VERSION 5.7 ;
BUSBITCHARS "[]" ;
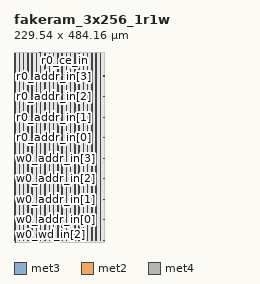
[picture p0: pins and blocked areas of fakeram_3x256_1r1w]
MACRO fakeram_3x256_1r1w
  FOREIGN fakeram_3x256_1r1w 0 0 ;
  SYMMETRY X Y R90 ;
  SIZE 229.540 BY 484.160 ;
  CLASS BLOCK ;
  PIN w0_wd_in[0]
    DIRECTION INPUT ;
    USE SIGNAL ;
    SHAPE ABUTMENT ;
    PORT
      LAYER met3 ;
      RECT 0.000 3.930 0.900 4.230 ;
    END
  END w0_wd_in[0]
  PIN w0_wd_in[1]
    DIRECTION INPUT ;
    USE SIGNAL ;
    SHAPE ABUTMENT ;
    PORT
      LAYER met3 ;
      RECT 228.640 3.930 229.540 4.230 ;
    END
  END w0_wd_in[1]
  PIN w0_wd_in[2]
    DIRECTION OUTPUT ;
    USE SIGNAL ;
    SHAPE ABUTMENT ;
    PORT
      LAYER met2 ;
      RECT 2.690 0.000 2.830 0.420 ;
    END
  END w0_wd_in[2]
  PIN r0_rd_out[0]
    DIRECTION OUTPUT ;
    USE SIGNAL ;
    SHAPE ABUTMENT ;
    PORT
      LAYER met2 ;
      RECT 58.350 0.000 58.490 0.420 ;
    END
  END r0_rd_out[0]
  PIN r0_rd_out[1]
    DIRECTION OUTPUT ;
    USE SIGNAL ;
    SHAPE ABUTMENT ;
    PORT
      LAYER met2 ;
      RECT 114.010 0.000 114.150 0.420 ;
    END
  END r0_rd_out[1]
  PIN r0_rd_out[2]
    DIRECTION OUTPUT ;
    USE SIGNAL ;
    SHAPE ABUTMENT ;
    PORT
      LAYER met2 ;
      RECT 2.690 483.740 2.830 484.160 ;
    END
  END r0_rd_out[2]
  PIN w0_addr_in[0]
    DIRECTION INPUT ;
    USE SIGNAL ;
    SHAPE ABUTMENT ;
    PORT
      LAYER met3 ;
      RECT 0.000 56.290 0.900 56.590 ;
    END
  END w0_addr_in[0]
  PIN w0_addr_in[1]
    DIRECTION INPUT ;
    USE SIGNAL ;
    SHAPE ABUTMENT ;
    PORT
      LAYER met3 ;
      RECT 0.000 108.650 0.900 108.950 ;
    END
  END w0_addr_in[1]
  PIN w0_addr_in[2]
    DIRECTION INPUT ;
    USE SIGNAL ;
    SHAPE ABUTMENT ;
    PORT
      LAYER met3 ;
      RECT 0.000 161.010 0.900 161.310 ;
    END
  END w0_addr_in[2]
  PIN w0_addr_in[3]
    DIRECTION INPUT ;
    USE SIGNAL ;
    SHAPE ABUTMENT ;
    PORT
      LAYER met3 ;
      RECT 0.000 213.370 0.900 213.670 ;
    END
  END w0_addr_in[3]
  PIN w0_addr_in[4]
    DIRECTION INPUT ;
    USE SIGNAL ;
    SHAPE ABUTMENT ;
    PORT
      LAYER met3 ;
      RECT 228.640 56.290 229.540 56.590 ;
    END
  END w0_addr_in[4]
  PIN w0_addr_in[5]
    DIRECTION INPUT ;
    USE SIGNAL ;
    SHAPE ABUTMENT ;
    PORT
      LAYER met3 ;
      RECT 228.640 108.650 229.540 108.950 ;
    END
  END w0_addr_in[5]
  PIN w0_addr_in[6]
    DIRECTION INPUT ;
    USE SIGNAL ;
    SHAPE ABUTMENT ;
    PORT
      LAYER met3 ;
      RECT 228.640 161.010 229.540 161.310 ;
    END
  END w0_addr_in[6]
  PIN w0_addr_in[7]
    DIRECTION INPUT ;
    USE SIGNAL ;
    SHAPE ABUTMENT ;
    PORT
      LAYER met3 ;
      RECT 228.640 213.370 229.540 213.670 ;
    END
  END w0_addr_in[7]
  PIN r0_addr_in[0]
    DIRECTION INPUT ;
    USE SIGNAL ;
    SHAPE ABUTMENT ;
    PORT
      LAYER met3 ;
      RECT 0.000 265.730 0.900 266.030 ;
    END
  END r0_addr_in[0]
  PIN r0_addr_in[1]
    DIRECTION INPUT ;
    USE SIGNAL ;
    SHAPE ABUTMENT ;
    PORT
      LAYER met3 ;
      RECT 0.000 318.090 0.900 318.390 ;
    END
  END r0_addr_in[1]
  PIN r0_addr_in[2]
    DIRECTION INPUT ;
    USE SIGNAL ;
    SHAPE ABUTMENT ;
    PORT
      LAYER met3 ;
      RECT 0.000 370.450 0.900 370.750 ;
    END
  END r0_addr_in[2]
  PIN r0_addr_in[3]
    DIRECTION INPUT ;
    USE SIGNAL ;
    SHAPE ABUTMENT ;
    PORT
      LAYER met3 ;
      RECT 0.000 422.810 0.900 423.110 ;
    END
  END r0_addr_in[3]
  PIN r0_addr_in[4]
    DIRECTION INPUT ;
    USE SIGNAL ;
    SHAPE ABUTMENT ;
    PORT
      LAYER met3 ;
      RECT 228.640 265.730 229.540 266.030 ;
    END
  END r0_addr_in[4]
  PIN r0_addr_in[5]
    DIRECTION INPUT ;
    USE SIGNAL ;
    SHAPE ABUTMENT ;
    PORT
      LAYER met3 ;
      RECT 228.640 318.090 229.540 318.390 ;
    END
  END r0_addr_in[5]
  PIN r0_addr_in[6]
    DIRECTION INPUT ;
    USE SIGNAL ;
    SHAPE ABUTMENT ;
    PORT
      LAYER met3 ;
      RECT 228.640 370.450 229.540 370.750 ;
    END
  END r0_addr_in[6]
  PIN r0_addr_in[7]
    DIRECTION INPUT ;
    USE SIGNAL ;
    SHAPE ABUTMENT ;
    PORT
      LAYER met3 ;
      RECT 228.640 422.810 229.540 423.110 ;
    END
  END r0_addr_in[7]
  PIN w0_we_in
    DIRECTION INPUT ;
    USE SIGNAL ;
    SHAPE ABUTMENT ;
    PORT
      LAYER met2 ;
      RECT 34.430 483.740 34.570 484.160 ;
    END
  END w0_we_in
  PIN w0_ce_in
    DIRECTION INPUT ;
    USE SIGNAL ;
    SHAPE ABUTMENT ;
    PORT
      LAYER met2 ;
      RECT 66.170 483.740 66.310 484.160 ;
    END
  END w0_ce_in
  PIN w0_clk
    DIRECTION INPUT ;
    USE SIGNAL ;
    SHAPE ABUTMENT ;
    PORT
      LAYER met2 ;
      RECT 97.910 483.740 98.050 484.160 ;
    END
  END w0_clk
  PIN r0_ce_in
    DIRECTION INPUT ;
    USE SIGNAL ;
    SHAPE ABUTMENT ;
    PORT
      LAYER met2 ;
      RECT 129.650 483.740 129.790 484.160 ;
    END
  END r0_ce_in
  PIN r0_clk
    DIRECTION INPUT ;
    USE SIGNAL ;
    SHAPE ABUTMENT ;
    PORT
      LAYER met2 ;
      RECT 161.390 483.740 161.530 484.160 ;
    END
  END r0_clk
  PIN VSS
    DIRECTION INOUT ;
    USE GROUND ;
    PORT
      LAYER met4 ;
      RECT 2.160 4.080 3.360 480.080 ;
      RECT 13.040 4.080 14.240 480.080 ;
      RECT 23.920 4.080 25.120 480.080 ;
      RECT 34.800 4.080 36.000 480.080 ;
      RECT 45.680 4.080 46.880 480.080 ;
      RECT 56.560 4.080 57.760 480.080 ;
      RECT 67.440 4.080 68.640 480.080 ;
      RECT 78.320 4.080 79.520 480.080 ;
      RECT 89.200 4.080 90.400 480.080 ;
      RECT 100.080 4.080 101.280 480.080 ;
      RECT 110.960 4.080 112.160 480.080 ;
      RECT 121.840 4.080 123.040 480.080 ;
      RECT 132.720 4.080 133.920 480.080 ;
      RECT 143.600 4.080 144.800 480.080 ;
      RECT 154.480 4.080 155.680 480.080 ;
      RECT 165.360 4.080 166.560 480.080 ;
      RECT 176.240 4.080 177.440 480.080 ;
      RECT 187.120 4.080 188.320 480.080 ;
      RECT 198.000 4.080 199.200 480.080 ;
      RECT 208.880 4.080 210.080 480.080 ;
      RECT 219.760 4.080 220.960 480.080 ;
    END
  END VSS
  PIN VDD
    DIRECTION INOUT ;
    USE POWER ;
    PORT
      LAYER met4 ;
      RECT 2.160 4.080 3.360 480.080 ;
      RECT 13.040 4.080 14.240 480.080 ;
      RECT 23.920 4.080 25.120 480.080 ;
      RECT 34.800 4.080 36.000 480.080 ;
      RECT 45.680 4.080 46.880 480.080 ;
      RECT 56.560 4.080 57.760 480.080 ;
      RECT 67.440 4.080 68.640 480.080 ;
      RECT 78.320 4.080 79.520 480.080 ;
      RECT 89.200 4.080 90.400 480.080 ;
      RECT 100.080 4.080 101.280 480.080 ;
      RECT 110.960 4.080 112.160 480.080 ;
      RECT 121.840 4.080 123.040 480.080 ;
      RECT 132.720 4.080 133.920 480.080 ;
      RECT 143.600 4.080 144.800 480.080 ;
      RECT 154.480 4.080 155.680 480.080 ;
      RECT 165.360 4.080 166.560 480.080 ;
      RECT 176.240 4.080 177.440 480.080 ;
      RECT 187.120 4.080 188.320 480.080 ;
      RECT 198.000 4.080 199.200 480.080 ;
      RECT 208.880 4.080 210.080 480.080 ;
      RECT 219.760 4.080 220.960 480.080 ;
    END
  END VDD
  OBS
    LAYER met1 ;
    RECT 0 0 229.540 484.160 ;
    LAYER met2 ;
    RECT 0 0 229.540 484.160 ;
    LAYER met3 ;
    RECT 0 0 229.540 484.160 ;
    LAYER met4 ;
    RECT 0 0 229.540 484.160 ;
  END
END fakeram_3x256_1r1w

END LIBRARY
